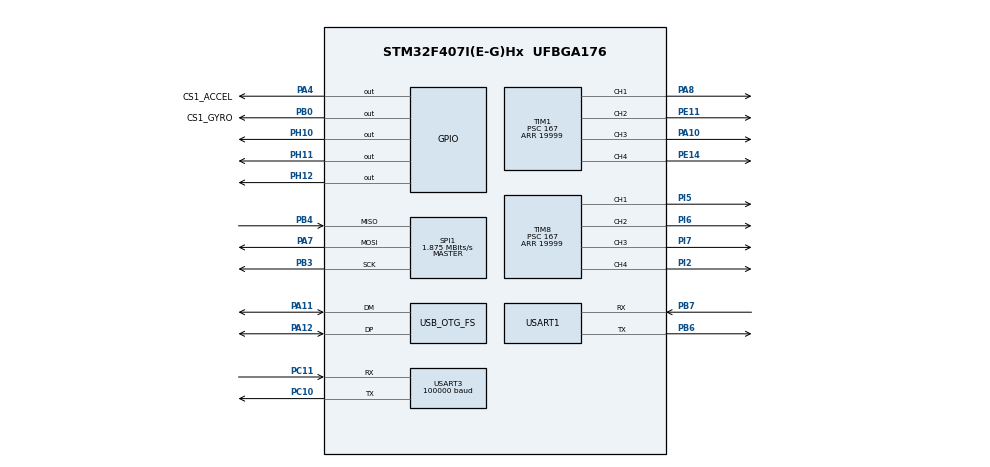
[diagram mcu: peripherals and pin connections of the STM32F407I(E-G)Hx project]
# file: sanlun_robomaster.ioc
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Dma.Request0=USART3_RX
Dma.USART3_RX.0.Direction=DMA_PERIPH_TO_MEMORY
Dma.USART3_RX.0.FIFOMode=DMA_FIFOMODE_DISABLE
Dma.USART3_RX.0.Instance=DMA1_Stream1
Dma.USART3_RX.0.MemDataAlignment=DMA_MDATAALIGN_BYTE
Dma.USART3_RX.0.MemInc=DMA_MINC_ENABLE
Dma.USART3_RX.0.Mode=DMA_NORMAL
Dma.USART3_RX.0.PeriphDataAlignment=DMA_PDATAALIGN_BYTE
Dma.USART3_RX.0.PeriphInc=DMA_PINC_DISABLE
Dma.USART3_RX.0.Priority=DMA_PRIORITY_LOW
FREERTOS.Tasks01=LedTask,-2,128,StartDefaultTask,Default,NULL,Dynamic,NULL,NULL;ControlTask,2,128,StartTask02,Default,NULL,Dynamic,NULL,NULL;ImuTask,3,512,StartTask03,Default,NULL,Dynamic,NULL,NULL
FREERTOS.configTOTAL_HEAP_SIZE=30720
Mcu.Family=STM32F4
Mcu.Name=STM32F407I(E-G)Hx
Mcu.Package=UFBGA176
NVIC.DMA1_Stream1_IRQn=true\:5\:0\:false\:false\:true\:true\:false\:true\:true
NVIC.OTG_FS_IRQn=true\:5\:0\:false\:false\:true\:true\:false\:true\:true
NVIC.PriorityGroup=NVIC_PRIORITYGROUP_4
NVIC.TIM7_IRQn=true\:15\:0\:false\:false\:true\:false\:false\:true\:true
NVIC.TimeBase=TIM7_IRQn
NVIC.TimeBaseIP=TIM7
NVIC.USART3_IRQn=true\:5\:0\:false\:false\:true\:true\:true\:true\:true
PA10.Signal=S_TIM1_CH3
PA11.Mode=Device_Only
PA11.Signal=USB_OTG_FS_DM
PA12.Mode=Device_Only
PA12.Signal=USB_OTG_FS_DP
PA13.Mode=Serial_Wire
PA13.Signal=SYS_JTMS-SWDIO
PA14.Mode=Serial_Wire
PA14.Signal=SYS_JTCK-SWCLK
PA4.GPIO_Label=CS1_ACCEL
PA4.PinState=GPIO_PIN_SET
PA4.Signal=GPIO_Output
PA7.Mode=Full_Duplex_Master
PA7.Signal=SPI1_MOSI
PA8.Signal=S_TIM1_CH1
PB0.GPIO_Label=CS1_GYRO
PB0.PinState=GPIO_PIN_SET
PB0.Signal=GPIO_Output
PB3.Mode=Full_Duplex_Master
PB3.Signal=SPI1_SCK
PB4.Mode=Full_Duplex_Master
PB4.Signal=SPI1_MISO
PB6.Mode=Asynchronous
PB6.Signal=USART1_TX
PB7.Mode=Asynchronous
PB7.Signal=USART1_RX
PC10.Mode=Asynchronous
PC10.Signal=USART3_TX
PC11.Mode=Asynchronous
PC11.Signal=USART3_RX
PE11.Signal=S_TIM1_CH2
PE14.Signal=S_TIM1_CH4
PH0-OSC_IN.Mode=HSE-External-Oscillator
PH0-OSC_IN.Signal=RCC_OSC_IN
PH1-OSC_OUT.Mode=HSE-External-Oscillator
PH1-OSC_OUT.Signal=RCC_OSC_OUT
PH10.GPIO_ModeDefaultOutputPP=GPIO_MODE_OUTPUT_PP
PH10.GPIO_PuPd=GPIO_NOPULL
PH10.GPIO_Speed=GPIO_SPEED_FREQ_LOW
PH10.PinState=GPIO_PIN_SET
PH10.Signal=GPIO_Output
PH11.GPIO_ModeDefaultOutputPP=GPIO_MODE_OUTPUT_PP
PH11.GPIO_PuPd=GPIO_NOPULL
PH11.GPIO_Speed=GPIO_SPEED_FREQ_LOW
PH11.PinState=GPIO_PIN_SET
PH11.Signal=GPIO_Output
PH12.Signal=GPIO_Output
PI2.Signal=S_TIM8_CH4
PI5.Signal=S_TIM8_CH1
PI6.Signal=S_TIM8_CH2
PI7.Signal=S_TIM8_CH3
ProjectManager.HeapSize=0x1000
ProjectManager.StackSize=0x400
ProjectManager.TargetToolchain=MDK-ARM V5.32
RCC.48MHZClocksFreq_Value=48000000
RCC.AHBFreq_Value=120000000
RCC.APB1CLKDivider=RCC_HCLK_DIV4
RCC.APB1Freq_Value=30000000
RCC.APB1TimFreq_Value=60000000
RCC.APB2CLKDivider=RCC_HCLK_DIV2
RCC.APB2Freq_Value=60000000
RCC.APB2TimFreq_Value=120000000
RCC.CortexFreq_Value=120000000
RCC.HCLKFreq_Value=120000000
RCC.HSE_VALUE=25000000
RCC.HSI_VALUE=16000000
RCC.LSE_VALUE=32768
RCC.PLLM=15
RCC.PLLN=144
RCC.PLLQ=5
RCC.SYSCLKFreq_VALUE=120000000
RCC.SYSCLKSource=RCC_SYSCLKSOURCE_PLLCLK
RCC.VCOOutputFreq_Value=240000000
SH.S_TIM1_CH1.0=TIM1_CH1,PWM Generation1 CH1
SH.S_TIM1_CH2.0=TIM1_CH2,PWM Generation2 CH2
SH.S_TIM1_CH3.0=TIM1_CH3,PWM Generation3 CH3
SH.S_TIM1_CH4.0=TIM1_CH4,PWM Generation4 CH4
SH.S_TIM8_CH1.0=TIM8_CH1,PWM Generation1 CH1
SH.S_TIM8_CH2.0=TIM8_CH2,PWM Generation2 CH2
SH.S_TIM8_CH3.0=TIM8_CH3,PWM Generation3 CH3
SH.S_TIM8_CH4.0=TIM8_CH4,PWM Generation4 CH4
SPI1.BaudRatePrescaler=SPI_BAUDRATEPRESCALER_32
SPI1.CLKPhase=SPI_PHASE_2EDGE
SPI1.CLKPolarity=SPI_POLARITY_HIGH
SPI1.CalculateBaudRate=1.875 MBits/s
SPI1.Direction=SPI_DIRECTION_2LINES
SPI1.Mode=SPI_MODE_MASTER
SPI1.VirtualType=VM_MASTER
TIM1.Channel-PWM\ Generation1\ CH1=TIM_CHANNEL_1
TIM1.Channel-PWM\ Generation2\ CH2=TIM_CHANNEL_2
TIM1.Channel-PWM\ Generation3\ CH3=TIM_CHANNEL_3
TIM1.Channel-PWM\ Generation4\ CH4=TIM_CHANNEL_4
TIM1.Period=19999
TIM1.Prescaler=167
TIM8.Channel-PWM\ Generation1\ CH1=TIM_CHANNEL_1
TIM8.Channel-PWM\ Generation2\ CH2=TIM_CHANNEL_2
TIM8.Channel-PWM\ Generation3\ CH3=TIM_CHANNEL_3
TIM8.Channel-PWM\ Generation4\ CH4=TIM_CHANNEL_4
TIM8.Period=19999
TIM8.Prescaler=167
USART1.VirtualMode=VM_ASYNC
USART3.BaudRate=100000
USART3.Parity=PARITY_EVEN
USART3.StopBits=STOPBITS_2
USART3.VirtualMode=VM_ASYNC
USART3.WordLength=WORDLENGTH_9B
USB_DEVICE.CLASS_NAME_FS=CDC
USB_DEVICE.VirtualMode-CDC_FS=Cdc
USB_DEVICE.VirtualModeFS=Cdc_FS
USB_OTG_FS.VirtualMode=Device_Only
VP_FREERTOS_VS_CMSIS_V1.Mode=CMSIS_V1
VP_SYS_VS_tim7.Mode=TIM7
VP_USB_DEVICE_VS_USB_DEVICE_CDC_FS.Mode=CDC_FS
board=custom

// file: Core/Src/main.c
/* USER CODE BEGIN Header */
/**
  ******************************************************************************
  * @file           : main.c
  * @brief          : Main program body
  ******************************************************************************
  * @attention
  *
  * Copyright (c) 2026 STMicroelectronics.
  * All rights reserved.
  *
  * This software is licensed under terms that can be found in the LICENSE file
  * in the root directory of this software component.
  * If no LICENSE file comes with this software, it is provided AS-IS.
  *
  ******************************************************************************
  */
/* USER CODE END Header */
#include "main.h"
#include "cmsis_os.h"
#include "usb_device.h"

/* USER CODE BEGIN Includes */
#include "sbus.h"
#include "servo.h"
#include "usbd_cdc_if.h"
extern USBD_HandleTypeDef hUsbDeviceFS;
/* USER CODE END Includes */

/* USER CODE BEGIN PD */
#define TRIM_M1  30  // 1号大轮的专属补偿值 (请根据实际情况改动)
#define TRIM_M3  30  // 3号小轮的专属补偿值
#define TRIM_M4  30  // 4号小轮的专属补偿值
/* USER CODE END PD */

SPI_HandleTypeDef hspi1;

TIM_HandleTypeDef htim1;
TIM_HandleTypeDef htim8;

UART_HandleTypeDef huart1;
UART_HandleTypeDef huart3;
DMA_HandleTypeDef hdma_usart3_rx;

osThreadId LedTaskHandle;
osThreadId ControlTaskHandle;
osThreadId ImuTaskHandle;

void SystemClock_Config(void);
static void MX_GPIO_Init(void);
static void MX_DMA_Init(void);
static void MX_TIM1_Init(void);
static void MX_TIM8_Init(void);
static void MX_USART1_UART_Init(void);
static void MX_USART3_UART_Init(void);
static void MX_SPI1_Init(void);
void StartDefaultTask(void const * argument);
void StartTask02(void const * argument);
void StartTask03(void const * argument);

int main(void)
{

  /* MCU Configuration--------------------------------------------------------*/

  /* Reset of all peripherals, Initializes the Flash interface and the Systick. */
  HAL_Init();

  /* Configure the system clock */
  SystemClock_Config();

  /* Initialize all configured peripherals */
  MX_GPIO_Init();
  MX_DMA_Init();
  MX_TIM1_Init();
  MX_TIM8_Init();
  MX_USART1_UART_Init();
  MX_USART3_UART_Init();
  MX_SPI1_Init();
  /* USER CODE BEGIN 2 */
  // 初始化SBUS和舵机
  SBUS_Init();
  Servo_Init();
  /* USER CODE END 2 */

  /* Create the thread(s) */
  /* definition and creation of LedTask */
  osThreadDef(LedTask, StartDefaultTask, osPriorityLow, 0, 128);
  LedTaskHandle = osThreadCreate(osThread(LedTask), NULL);

  /* definition and creation of ControlTask */
  osThreadDef(ControlTask, StartControlTask, osPriorityHigh, 0, 128);
  ControlTaskHandle = osThreadCreate(osThread(ControlTask), NULL);

  /* definition and creation of ImuTask */
  osThreadDef(ImuTask, StartIMUTask, osPriorityRealtime, 0, 512);
  ImuTaskHandle = osThreadCreate(osThread(ImuTask), NULL);

  /* Start scheduler */
  osKernelStart();

  /* We should never get here as control is now taken by the scheduler */

  /* Infinite loop */
  while (1)
  {

  }
}

void SystemClock_Config(void)
{
  RCC_OscInitTypeDef RCC_OscInitStruct = {0};
  RCC_ClkInitTypeDef RCC_ClkInitStruct = {0};

  /** Configure the main internal regulator output voltage
  */
  __HAL_RCC_PWR_CLK_ENABLE();
  __HAL_PWR_VOLTAGESCALING_CONFIG(PWR_REGULATOR_VOLTAGE_SCALE1);

  /** Initializes the RCC Oscillators according to the specified parameters
  * in the RCC_OscInitTypeDef structure.
  */
  RCC_OscInitStruct.OscillatorType = RCC_OSCILLATORTYPE_HSE;
  RCC_OscInitStruct.HSEState = RCC_HSE_ON;
  RCC_OscInitStruct.PLL.PLLState = RCC_PLL_ON;
  RCC_OscInitStruct.PLL.PLLSource = RCC_PLLSOURCE_HSE;
  RCC_OscInitStruct.PLL.PLLM = 6;
  RCC_OscInitStruct.PLL.PLLN = 168;
  RCC_OscInitStruct.PLL.PLLP = RCC_PLLP_DIV2;
  RCC_OscInitStruct.PLL.PLLQ = 7;
  if (HAL_RCC_OscConfig(&RCC_OscInitStruct) != HAL_OK)
  {
    Error_Handler();
  }

  /** Initializes the CPU, AHB and APB buses clocks
  */
  RCC_ClkInitStruct.ClockType = RCC_CLOCKTYPE_HCLK|RCC_CLOCKTYPE_SYSCLK
                              |RCC_CLOCKTYPE_PCLK1|RCC_CLOCKTYPE_PCLK2;
  RCC_ClkInitStruct.SYSCLKSource = RCC_SYSCLKSOURCE_PLLCLK;
  RCC_ClkInitStruct.AHBCLKDivider = RCC_SYSCLK_DIV1;
  RCC_ClkInitStruct.APB1CLKDivider = RCC_HCLK_DIV4;
  RCC_ClkInitStruct.APB2CLKDivider = RCC_HCLK_DIV2;

  if (HAL_RCC_ClockConfig(&RCC_ClkInitStruct, FLASH_LATENCY_5) != HAL_OK)
  {
    Error_Handler();
  }
}

static void MX_SPI1_Init(void)
{

  /* SPI1 parameter configuration*/
  hspi1.Instance = SPI1;
  hspi1.Init.Mode = SPI_MODE_MASTER;
  hspi1.Init.Direction = SPI_DIRECTION_2LINES;
  hspi1.Init.DataSize = SPI_DATASIZE_8BIT;
  hspi1.Init.CLKPolarity = SPI_POLARITY_HIGH;
  hspi1.Init.CLKPhase = SPI_PHASE_2EDGE;
  hspi1.Init.NSS = SPI_NSS_SOFT;
  hspi1.Init.BaudRatePrescaler = SPI_BAUDRATEPRESCALER_32;
  hspi1.Init.FirstBit = SPI_FIRSTBIT_MSB;
  hspi1.Init.TIMode = SPI_TIMODE_DISABLE;
  hspi1.Init.CRCCalculation = SPI_CRCCALCULATION_DISABLE;
  hspi1.Init.CRCPolynomial = 10;
  if (HAL_SPI_Init(&hspi1) != HAL_OK)
  {
    Error_Handler();
  }

}

static void MX_TIM1_Init(void)
{

  TIM_MasterConfigTypeDef sMasterConfig = {0};
  TIM_OC_InitTypeDef sConfigOC = {0};
  TIM_BreakDeadTimeConfigTypeDef sBreakDeadTimeConfig = {0};

  htim1.Instance = TIM1;
  htim1.Init.Prescaler = 167;
  htim1.Init.CounterMode = TIM_COUNTERMODE_UP;
  htim1.Init.Period = 19999;
  htim1.Init.ClockDivision = TIM_CLOCKDIVISION_DIV1;
  htim1.Init.RepetitionCounter = 0;
  htim1.Init.AutoReloadPreload = TIM_AUTORELOAD_PRELOAD_DISABLE;
  if (HAL_TIM_PWM_Init(&htim1) != HAL_OK)
  {
    Error_Handler();
  }
  sMasterConfig.MasterOutputTrigger = TIM_TRGO_RESET;
  sMasterConfig.MasterSlaveMode = TIM_MASTERSLAVEMODE_DISABLE;
  if (HAL_TIMEx_MasterConfigSynchronization(&htim1, &sMasterConfig) != HAL_OK)
  {
    Error_Handler();
  }
  sConfigOC.OCMode = TIM_OCMODE_PWM1;
  sConfigOC.Pulse = 0;
  sConfigOC.OCPolarity = TIM_OCPOLARITY_HIGH;
  sConfigOC.OCNPolarity = TIM_OCNPOLARITY_HIGH;
  sConfigOC.OCFastMode = TIM_OCFAST_DISABLE;
  sConfigOC.OCIdleState = TIM_OCIDLESTATE_RESET;
  sConfigOC.OCNIdleState = TIM_OCNIDLESTATE_RESET;
  if (HAL_TIM_PWM_ConfigChannel(&htim1, &sConfigOC, TIM_CHANNEL_1) != HAL_OK)
  {
    Error_Handler();
  }
  if (HAL_TIM_PWM_ConfigChannel(&htim1, &sConfigOC, TIM_CHANNEL_2) != HAL_OK)
  {
    Error_Handler();
  }
  if (HAL_TIM_PWM_ConfigChannel(&htim1, &sConfigOC, TIM_CHANNEL_3) != HAL_OK)
  {
    Error_Handler();
  }
  if (HAL_TIM_PWM_ConfigChannel(&htim1, &sConfigOC, TIM_CHANNEL_4) != HAL_OK)
  {
    Error_Handler();
  }
  sBreakDeadTimeConfig.OffStateRunMode = TIM_OSSR_DISABLE;
  sBreakDeadTimeConfig.OffStateIDLEMode = TIM_OSSI_DISABLE;
  sBreakDeadTimeConfig.LockLevel = TIM_LOCKLEVEL_OFF;
  sBreakDeadTimeConfig.DeadTime = 0;
  sBreakDeadTimeConfig.BreakState = TIM_BREAK_DISABLE;
  sBreakDeadTimeConfig.BreakPolarity = TIM_BREAKPOLARITY_HIGH;
  sBreakDeadTimeConfig.AutomaticOutput = TIM_AUTOMATICOUTPUT_DISABLE;
  if (HAL_TIMEx_ConfigBreakDeadTime(&htim1, &sBreakDeadTimeConfig) != HAL_OK)
  {
    Error_Handler();
  }
  HAL_TIM_MspPostInit(&htim1);

}

static void MX_TIM8_Init(void)
{

  TIM_MasterConfigTypeDef sMasterConfig = {0};
  TIM_OC_InitTypeDef sConfigOC = {0};
  TIM_BreakDeadTimeConfigTypeDef sBreakDeadTimeConfig = {0};

  htim8.Instance = TIM8;
  htim8.Init.Prescaler = 167;
  htim8.Init.CounterMode = TIM_COUNTERMODE_UP;
  htim8.Init.Period = 19999;
  htim8.Init.ClockDivision = TIM_CLOCKDIVISION_DIV1;
  htim8.Init.RepetitionCounter = 0;
  htim8.Init.AutoReloadPreload = TIM_AUTORELOAD_PRELOAD_DISABLE;
  if (HAL_TIM_PWM_Init(&htim8) != HAL_OK)
  {
    Error_Handler();
  }
  sMasterConfig.MasterOutputTrigger = TIM_TRGO_RESET;
  sMasterConfig.MasterSlaveMode = TIM_MASTERSLAVEMODE_DISABLE;
  if (HAL_TIMEx_MasterConfigSynchronization(&htim8, &sMasterConfig) != HAL_OK)
  {
    Error_Handler();
  }
  sConfigOC.OCMode = TIM_OCMODE_PWM1;
  sConfigOC.Pulse = 0;
  sConfigOC.OCPolarity = TIM_OCPOLARITY_HIGH;
  sConfigOC.OCNPolarity = TIM_OCNPOLARITY_HIGH;
  sConfigOC.OCFastMode = TIM_OCFAST_DISABLE;
  sConfigOC.OCIdleState = TIM_OCIDLESTATE_RESET;
  sConfigOC.OCNIdleState = TIM_OCNIDLESTATE_RESET;
  if (HAL_TIM_PWM_ConfigChannel(&htim8, &sConfigOC, TIM_CHANNEL_1) != HAL_OK)
  {
    Error_Handler();
  }
  if (HAL_TIM_PWM_ConfigChannel(&htim8, &sConfigOC, TIM_CHANNEL_2) != HAL_OK)
  {
    Error_Handler();
  }
  if (HAL_TIM_PWM_ConfigChannel(&htim8, &sConfigOC, TIM_CHANNEL_3) != HAL_OK)
  {
    Error_Handler();
  }
  if (HAL_TIM_PWM_ConfigChannel(&htim8, &sConfigOC, TIM_CHANNEL_4) != HAL_OK)
  {
    Error_Handler();
  }
  sBreakDeadTimeConfig.OffStateRunMode = TIM_OSSR_DISABLE;
  sBreakDeadTimeConfig.OffStateIDLEMode = TIM_OSSI_DISABLE;
  sBreakDeadTimeConfig.LockLevel = TIM_LOCKLEVEL_OFF;
  sBreakDeadTimeConfig.DeadTime = 0;
  sBreakDeadTimeConfig.BreakState = TIM_BREAK_DISABLE;
  sBreakDeadTimeConfig.BreakPolarity = TIM_BREAKPOLARITY_HIGH;
  sBreakDeadTimeConfig.AutomaticOutput = TIM_AUTOMATICOUTPUT_DISABLE;
  if (HAL_TIMEx_ConfigBreakDeadTime(&htim8, &sBreakDeadTimeConfig) != HAL_OK)
  {
    Error_Handler();
  }
  HAL_TIM_MspPostInit(&htim8);

}

static void MX_USART1_UART_Init(void)
{

  huart1.Instance = USART1;
  huart1.Init.BaudRate = 115200;
  huart1.Init.WordLength = UART_WORDLENGTH_8B;
  huart1.Init.StopBits = UART_STOPBITS_1;
  huart1.Init.Parity = UART_PARITY_NONE;
  huart1.Init.Mode = UART_MODE_TX_RX;
  huart1.Init.HwFlowCtl = UART_HWCONTROL_NONE;
  huart1.Init.OverSampling = UART_OVERSAMPLING_16;
  if (HAL_UART_Init(&huart1) != HAL_OK)
  {
    Error_Handler();
  }

}

static void MX_USART3_UART_Init(void)
{

  huart3.Instance = USART3;
  huart3.Init.BaudRate = 100000;
  huart3.Init.WordLength = UART_WORDLENGTH_9B;
  huart3.Init.StopBits = UART_STOPBITS_2;
  huart3.Init.Parity = UART_PARITY_EVEN;
  huart3.Init.Mode = UART_MODE_TX_RX;
  huart3.Init.HwFlowCtl = UART_HWCONTROL_NONE;
  huart3.Init.OverSampling = UART_OVERSAMPLING_16;
  if (HAL_UART_Init(&huart3) != HAL_OK)
  {
    Error_Handler();
  }

}

static void MX_DMA_Init(void)
{

  /* DMA controller clock enable */
  __HAL_RCC_DMA1_CLK_ENABLE();

  /* DMA interrupt init */
  /* DMA1_Stream1_IRQn interrupt configuration */
  HAL_NVIC_SetPriority(DMA1_Stream1_IRQn, 5, 0);
  HAL_NVIC_EnableIRQ(DMA1_Stream1_IRQn);

}

static void MX_GPIO_Init(void)
{
  GPIO_InitTypeDef GPIO_InitStruct = {0};

  /* GPIO Ports Clock Enable */
  __HAL_RCC_GPIOB_CLK_ENABLE();
  __HAL_RCC_GPIOA_CLK_ENABLE();
  __HAL_RCC_GPIOC_CLK_ENABLE();
  __HAL_RCC_GPIOI_CLK_ENABLE();
  __HAL_RCC_GPIOH_CLK_ENABLE();
  __HAL_RCC_GPIOE_CLK_ENABLE();

  /*Configure GPIO pin Output Level */
  HAL_GPIO_WritePin(GPIOH, GPIO_PIN_12, GPIO_PIN_RESET);

  /*Configure GPIO pin Output Level */
  HAL_GPIO_WritePin(GPIOH, GPIO_PIN_11|GPIO_PIN_10, GPIO_PIN_SET);

  /*Configure GPIO pin Output Level */
  HAL_GPIO_WritePin(CS1_ACCEL_GPIO_Port, CS1_ACCEL_Pin, GPIO_PIN_SET);

  /*Configure GPIO pin Output Level */
  HAL_GPIO_WritePin(CS1_GYRO_GPIO_Port, CS1_GYRO_Pin, GPIO_PIN_SET);

  /*Configure GPIO pins : PH12 PH11 PH10 */
  GPIO_InitStruct.Pin = GPIO_PIN_12|GPIO_PIN_11|GPIO_PIN_10;
  GPIO_InitStruct.Mode = GPIO_MODE_OUTPUT_PP;
  GPIO_InitStruct.Pull = GPIO_NOPULL;
  GPIO_InitStruct.Speed = GPIO_SPEED_FREQ_LOW;
  HAL_GPIO_Init(GPIOH, &GPIO_InitStruct);

  /*Configure GPIO pin : CS1_ACCEL_Pin */
  GPIO_InitStruct.Pin = CS1_ACCEL_Pin;
  GPIO_InitStruct.Mode = GPIO_MODE_OUTPUT_PP;
  GPIO_InitStruct.Pull = GPIO_NOPULL;
  GPIO_InitStruct.Speed = GPIO_SPEED_FREQ_LOW;
  HAL_GPIO_Init(CS1_ACCEL_GPIO_Port, &GPIO_InitStruct);

  /*Configure GPIO pin : CS1_GYRO_Pin */
  GPIO_InitStruct.Pin = CS1_GYRO_Pin;
  GPIO_InitStruct.Mode = GPIO_MODE_OUTPUT_PP;
  GPIO_InitStruct.Pull = GPIO_NOPULL;
  GPIO_InitStruct.Speed = GPIO_SPEED_FREQ_LOW;
  HAL_GPIO_Init(CS1_GYRO_GPIO_Port, &GPIO_InitStruct);

}

void StartDefaultTask(void const * argument)
{
  /* init code for USB_DEVICE */
  MX_USB_DEVICE_Init();

  // 给电脑 2 秒识别时间
  osDelay(2000);

  /* USER CODE BEGIN 5 */
  char *test_str = "BINGO! USB IS ALIVE!\r\n";

  /* Infinite loop */
  for(;;)
  {
    // 1. 让蓝灯闪烁起来！(根据原理图，GPIOH10 是蓝灯)
    HAL_GPIO_TogglePin(GPIOH, GPIO_PIN_10);

    // 2. 安全发送 USB 数据
    if (hUsbDeviceFS.dev_state == USBD_STATE_CONFIGURED)
    {
        if (hUsbDeviceFS.pClassData != NULL)
        {
            USBD_CDC_HandleTypeDef *hcdc = (USBD_CDC_HandleTypeDef*)hUsbDeviceFS.pClassData;
            if (hcdc->TxState == 0)
            {
                extern uint8_t CDC_Transmit_FS(uint8_t* Buf, uint16_t Len);
                CDC_Transmit_FS((uint8_t*)test_str, strlen(test_str));
            }
        }
    }

    // 闪烁周期 500ms
    osDelay(500);
  }
  /* USER CODE END 5 */
}

void StartTask02(void const * argument)
{
  for(;;)
  {
    osDelay(1);
  }
}

void StartTask03(void const * argument)
{
  for(;;)
  {
    osDelay(1);
  }
}

void HAL_TIM_PeriodElapsedCallback(TIM_HandleTypeDef *htim)
{
  if (htim->Instance == TIM7) {
    HAL_IncTick();
  }
}

void Error_Handler(void)
{
  __disable_irq();
  while (1)
  {
  }
}

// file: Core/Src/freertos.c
/* USER CODE BEGIN Header */
/**
  ******************************************************************************
  * File Name          : freertos.c
  * Description        : Code for freertos applications
  ******************************************************************************
  * @attention
  *
  * Copyright (c) 2026 STMicroelectronics.
  * All rights reserved.
  *
  * This software is licensed under terms that can be found in the LICENSE file
  * in the root directory of this software component.
  * If no LICENSE file comes with this software, it is provided AS-IS.
  *
  ******************************************************************************
  */
/* USER CODE END Header */

#include "FreeRTOS.h"
#include "task.h"
#include "main.h"

/* USER CODE BEGIN Includes */
#include "cmsis_os.h"
#include "sbus.h"
#include "servo.h"
#include "BMI088driver.h"
#include <stdio.h>
#include <string.h>
#include "usbd_cdc_if.h"
extern USBD_HandleTypeDef hUsbDeviceFS;

/* ====== 360度舵机物理零点补偿 (软件微调) ====== */
#define TRIM_M1  30
#define TRIM_M3  30
#define TRIM_M4  30
/* USER CODE END Includes */

/* USER CODE BEGIN Variables */
fp32 INS_gyro[3] = {0.0f, 0.0f, 0.0f};
fp32 INS_accel[3] = {0.0f, 0.0f, 0.0f};
fp32 INS_temp = 0.0f;
/* USER CODE END Variables */

/* USER CODE BEGIN FunctionPrototypes */
void StartLedTask(void const * argument);
void StartControlTask(void const * argument);
void StartIMUTask(void const * argument);
/* USER CODE END FunctionPrototypes */

/* GetIdleTaskMemory prototype (linked to static allocation support) */
void vApplicationGetIdleTaskMemory( StaticTask_t **ppxIdleTaskTCBBuffer, StackType_t **ppxIdleTaskStackBuffer, uint32_t *pulIdleTaskStackSize );

/* USER CODE BEGIN GET_IDLE_TASK_MEMORY */
static StaticTask_t xIdleTaskTCBBuffer;
static StackType_t xIdleStack[configMINIMAL_STACK_SIZE];

void vApplicationGetIdleTaskMemory( StaticTask_t **ppxIdleTaskTCBBuffer, StackType_t **ppxIdleTaskStackBuffer, uint32_t *pulIdleTaskStackSize )
{
  *ppxIdleTaskTCBBuffer = &xIdleTaskTCBBuffer;
  *ppxIdleTaskStackBuffer = &xIdleStack[0];
  *pulIdleTaskStackSize = configMINIMAL_STACK_SIZE;
  /* place for user code */
}
/* USER CODE END GET_IDLE_TASK_MEMORY */

/* USER CODE BEGIN Application */

/* ========== Task 1: LED 心跳 ========== */
void StartLedTask(void const * argument)
{
  /* USER CODE BEGIN StartLedTask */
  for(;;)
  {
    HAL_GPIO_TogglePin(GPIOH, GPIO_PIN_10);  // 蓝灯闪烁 (系统心跳)
    osDelay(500);
  }
  /* USER CODE END StartLedTask */
}

/* ========== Task 2: 核心战车控制 ========== */
void StartControlTask(void const * argument)
{
  /* USER CODE BEGIN StartControlTask */
  for(;;)
  {
    // 1. 信号状态灯
    if(SBUS_IsValid()) {
      HAL_GPIO_WritePin(GPIOH, GPIO_PIN_12, GPIO_PIN_RESET);  // 绿灯常亮
      HAL_GPIO_WritePin(GPIOH, GPIO_PIN_11, GPIO_PIN_SET);    // 红灯灭
    } else {
      HAL_GPIO_WritePin(GPIOH, GPIO_PIN_12, GPIO_PIN_SET);    // 绿灯灭
      HAL_GPIO_WritePin(GPIOH, GPIO_PIN_11, GPIO_PIN_RESET);  // 红灯亮
    }

    SBUS_Process();

    // 2. 双模式遥控控制
    if (SBUS_IsValid())
    {
      int16_t channel1 = SBUS_GetChannel(1);
      int16_t channel2 = SBUS_GetChannel(2);
      int16_t channel3 = SBUS_GetChannel(3);
      int16_t channel9 = SBUS_GetChannel(9);
      int16_t channel5 = SBUS_GetChannel(5);

      if (channel9 < 1000)
      {
        // 模式1：同步驾驶模式 (左手上下方向，右手上下油门)
        int16_t drive_speed = 0;
        uint16_t steer_pulse = 1500;

        int16_t ch2_offset = channel2 - 1024;
        if (ch2_offset > -50 && ch2_offset < 50) {
          drive_speed = 0;
        } else if (ch2_offset >= 50) {
          drive_speed = (ch2_offset * 1000) / (1700 - 1024);
        } else {
          drive_speed = (ch2_offset * 1000) / (1024 - 300);
        }

        if (drive_speed > 1000) drive_speed = 1000;
        if (drive_speed < -1000) drive_speed = -1000;

        int16_t servo1_speed = (drive_speed * 50) / 63;

        Servo_Set360(1, servo1_speed + TRIM_M1);
        Servo_Set360(3, drive_speed + TRIM_M3);
        Servo_Set360(4, drive_speed + TRIM_M4);

        #define STEER_MIN_PULSE  500
        #define STEER_MAX_PULSE  2500

        int16_t ch3_offset = channel3 - 1024;
        if (ch3_offset > -30 && ch3_offset < 30) {
          steer_pulse = 1500;
        } else {
          steer_pulse = 1500 + (ch3_offset * 1000) / (1700 - 1024);
        }

        if (steer_pulse > STEER_MAX_PULSE) steer_pulse = STEER_MAX_PULSE;
        if (steer_pulse < STEER_MIN_PULSE) steer_pulse = STEER_MIN_PULSE;

        Servo_Set180(2, steer_pulse);
      }
      else
      {
        // 模式2：纯右手调试模式
        int16_t servo1_speed = 0;
        int16_t servo3_speed = 0;
        int16_t servo4_speed = 0;

        int16_t ch2_offset = channel2 - 1024;
        if (ch2_offset > -50 && ch2_offset < 50) servo1_speed = 0;
        else if (ch2_offset >= 50) servo1_speed = (ch2_offset * 1000) / (1700 - 1024);
        else servo1_speed = (ch2_offset * 1000) / (1024 - 300);

        int16_t ch1_offset = channel1 - 1024;
        int16_t ch1_speed = 0;
        if (ch1_offset > -50 && ch1_offset < 50) ch1_speed = 0;
        else if (ch1_offset >= 50) ch1_speed = (ch1_offset * 1000) / (1700 - 1024);
        else ch1_speed = (ch1_offset * 1000) / (1024 - 300);

        if (channel5 < 1000) {
          servo3_speed = ch1_speed;
        } else {
          servo4_speed = ch1_speed;
        }

        if (servo1_speed > 1000) servo1_speed = 1000; if (servo1_speed < -1000) servo1_speed = -1000;
        if (servo3_speed > 1000) servo3_speed = 1000; if (servo3_speed < -1000) servo3_speed = -1000;
        if (servo4_speed > 1000) servo4_speed = 1000; if (servo4_speed < -1000) servo4_speed = -1000;

        Servo_Set360(1, servo1_speed + TRIM_M1);
        Servo_Set360(3, servo3_speed + TRIM_M3);
        Servo_Set360(4, servo4_speed + TRIM_M4);

        Servo_Set180(2, 1500);
      }
    }
    else
    {
      // 失控保护
      Servo_Set360(1, TRIM_M1);
      Servo_Set360(3, TRIM_M3);
      Servo_Set360(4, TRIM_M4);
      Servo_Set180(2, 1500);
    }

    osDelay(10);
  }
  /* USER CODE END StartControlTask */
}

/* ========== Task 3: IMU 读取任务 ========== */
void StartIMUTask(void const * argument)
{
  // 1. 初始化大疆 IMU 核武器
  while (BMI088_init() != 0)
  {
      osDelay(50);
  }

  char usb_buf[128];

  for(;;)
  {
      // 2. 读取角速度和加速度
      BMI088_read(INS_gyro, INS_accel, &INS_temp);

      // 3. FireWater 协议格式
      sprintf(usb_buf, "%d,%d,%d,%d,%d,%d\n",
              (int)(INS_gyro[0] * 1000), (int)(INS_gyro[1] * 1000), (int)(INS_gyro[2] * 1000),
              (int)(INS_accel[0] * 1000), (int)(INS_accel[1] * 1000), (int)(INS_accel[2] * 1000));

      // 4. 终极防爆安全发送锁
      if (hUsbDeviceFS.dev_state == USBD_STATE_CONFIGURED)
      {
          if (hUsbDeviceFS.pClassData != NULL)
          {
              USBD_CDC_HandleTypeDef *hcdc = (USBD_CDC_HandleTypeDef*)hUsbDeviceFS.pClassData;
              if (hcdc->TxState == 0)
              {
                  extern uint8_t CDC_Transmit_FS(uint8_t* Buf, uint16_t Len);
                  CDC_Transmit_FS((uint8_t*)usb_buf, strlen(usb_buf));
              }
          }
      }

      osDelay(2);
  }
}

/* USER CODE END Application */
